VERSION 5.8 ;
BUSBITCHARS "[]" ;
DIVIDERCHAR "/" ;
UNITS
    DATABASE MICRONS 1000 ;
END UNITS

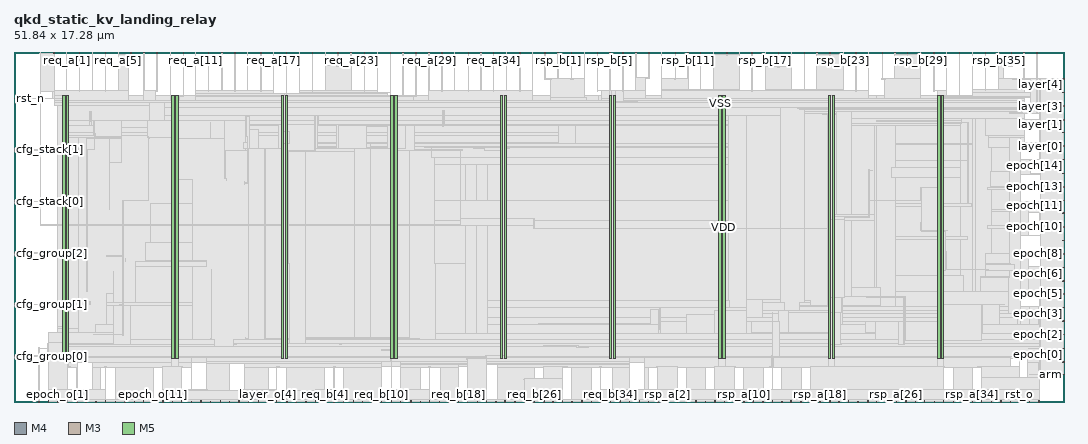
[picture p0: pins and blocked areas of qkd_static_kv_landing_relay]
MACRO qkd_static_kv_landing_relay
  FOREIGN qkd_static_kv_landing_relay 0 0 ;
  CLASS BLOCK ;
  SIZE 51.84 BY 17.28 ;
  PIN arm
    DIRECTION INPUT ;
    USE SIGNAL ;
    PORT
      LAYER M4 ;
        RECT  51.756 1.344 51.84 1.368 ;
    END
  END arm
  PIN arm_o
    DIRECTION OUTPUT ;
    USE SIGNAL ;
    PORT
      LAYER M3 ;
        RECT  1.224 0 1.242 0.038 ;
    END
  END arm_o
  PIN cfg_group[0]
    DIRECTION INPUT ;
    USE SIGNAL ;
    PORT
      LAYER M4 ;
        RECT  0 2.256 0.084 2.28 ;
    END
  END cfg_group[0]
  PIN cfg_group[1]
    DIRECTION INPUT ;
    USE SIGNAL ;
    PORT
      LAYER M4 ;
        RECT  0 4.8 0.084 4.824 ;
    END
  END cfg_group[1]
  PIN cfg_group[2]
    DIRECTION INPUT ;
    USE SIGNAL ;
    PORT
      LAYER M4 ;
        RECT  0 7.344 0.084 7.368 ;
    END
  END cfg_group[2]
  PIN cfg_stack[0]
    DIRECTION INPUT ;
    USE SIGNAL ;
    PORT
      LAYER M4 ;
        RECT  0 9.888 0.084 9.912 ;
    END
  END cfg_stack[0]
  PIN cfg_stack[1]
    DIRECTION INPUT ;
    USE SIGNAL ;
    PORT
      LAYER M4 ;
        RECT  0 12.432 0.084 12.456 ;
    END
  END cfg_stack[1]
  PIN ck
    DIRECTION INPUT ;
    USE SIGNAL ;
    PORT
      LAYER M3 ;
        RECT  1.296 17.242 1.314 17.28 ;
    END
  END ck
  PIN epoch[0]
    DIRECTION INPUT ;
    USE SIGNAL ;
    PORT
      LAYER M4 ;
        RECT  51.756 1.968 51.84 1.992 ;
    END
  END epoch[0]
  PIN epoch[10]
    DIRECTION INPUT ;
    USE SIGNAL ;
    PORT
      LAYER M4 ;
        RECT  51.756 8.64 51.84 8.664 ;
    END
  END epoch[10]
  PIN epoch[11]
    DIRECTION INPUT ;
    USE SIGNAL ;
    PORT
      LAYER M4 ;
        RECT  51.756 9.312 51.84 9.336 ;
    END
  END epoch[11]
  PIN epoch[12]
    DIRECTION INPUT ;
    USE SIGNAL ;
    PORT
      LAYER M4 ;
        RECT  51.756 9.936 51.84 9.96 ;
    END
  END epoch[12]
  PIN epoch[13]
    DIRECTION INPUT ;
    USE SIGNAL ;
    PORT
      LAYER M4 ;
        RECT  51.756 10.608 51.84 10.632 ;
    END
  END epoch[13]
  PIN epoch[14]
    DIRECTION INPUT ;
    USE SIGNAL ;
    PORT
      LAYER M4 ;
        RECT  51.756 11.28 51.84 11.304 ;
    END
  END epoch[14]
  PIN epoch[15]
    DIRECTION INPUT ;
    USE SIGNAL ;
    PORT
      LAYER M4 ;
        RECT  51.756 11.952 51.84 11.976 ;
    END
  END epoch[15]
  PIN epoch[1]
    DIRECTION INPUT ;
    USE SIGNAL ;
    PORT
      LAYER M4 ;
        RECT  51.756 2.64 51.84 2.664 ;
    END
  END epoch[1]
  PIN epoch[2]
    DIRECTION INPUT ;
    USE SIGNAL ;
    PORT
      LAYER M4 ;
        RECT  51.756 3.312 51.84 3.336 ;
    END
  END epoch[2]
  PIN epoch[3]
    DIRECTION INPUT ;
    USE SIGNAL ;
    PORT
      LAYER M4 ;
        RECT  51.756 3.984 51.84 4.008 ;
    END
  END epoch[3]
  PIN epoch[4]
    DIRECTION INPUT ;
    USE SIGNAL ;
    PORT
      LAYER M4 ;
        RECT  51.756 4.656 51.84 4.68 ;
    END
  END epoch[4]
  PIN epoch[5]
    DIRECTION INPUT ;
    USE SIGNAL ;
    PORT
      LAYER M4 ;
        RECT  51.756 5.328 51.84 5.352 ;
    END
  END epoch[5]
  PIN epoch[6]
    DIRECTION INPUT ;
    USE SIGNAL ;
    PORT
      LAYER M4 ;
        RECT  51.756 5.952 51.84 5.976 ;
    END
  END epoch[6]
  PIN epoch[7]
    DIRECTION INPUT ;
    USE SIGNAL ;
    PORT
      LAYER M4 ;
        RECT  51.756 6.624 51.84 6.648 ;
    END
  END epoch[7]
  PIN epoch[8]
    DIRECTION INPUT ;
    USE SIGNAL ;
    PORT
      LAYER M4 ;
        RECT  51.756 7.296 51.84 7.32 ;
    END
  END epoch[8]
  PIN epoch[9]
    DIRECTION INPUT ;
    USE SIGNAL ;
    PORT
      LAYER M4 ;
        RECT  51.756 7.968 51.84 7.992 ;
    END
  END epoch[9]
  PIN epoch_o[0]
    DIRECTION OUTPUT ;
    USE SIGNAL ;
    PORT
      LAYER M5 ;
        RECT  1.68 0 1.704 0.084 ;
    END
  END epoch_o[0]
  PIN epoch_o[10]
    DIRECTION OUTPUT ;
    USE SIGNAL ;
    PORT
      LAYER M5 ;
        RECT  6.384 0 6.408 0.084 ;
    END
  END epoch_o[10]
  PIN epoch_o[11]
    DIRECTION OUTPUT ;
    USE SIGNAL ;
    PORT
      LAYER M3 ;
        RECT  6.876 0 6.894 0.038 ;
    END
  END epoch_o[11]
  PIN epoch_o[12]
    DIRECTION OUTPUT ;
    USE SIGNAL ;
    PORT
      LAYER M5 ;
        RECT  7.344 0 7.368 0.084 ;
    END
  END epoch_o[12]
  PIN epoch_o[13]
    DIRECTION OUTPUT ;
    USE SIGNAL ;
    PORT
      LAYER M3 ;
        RECT  7.812 0 7.83 0.038 ;
    END
  END epoch_o[13]
  PIN epoch_o[14]
    DIRECTION OUTPUT ;
    USE SIGNAL ;
    PORT
      LAYER M5 ;
        RECT  8.256 0 8.28 0.084 ;
    END
  END epoch_o[14]
  PIN epoch_o[15]
    DIRECTION OUTPUT ;
    USE SIGNAL ;
    PORT
      LAYER M3 ;
        RECT  8.748 0 8.766 0.038 ;
    END
  END epoch_o[15]
  PIN epoch_o[1]
    DIRECTION OUTPUT ;
    USE SIGNAL ;
    PORT
      LAYER M3 ;
        RECT  2.16 0 2.178 0.038 ;
    END
  END epoch_o[1]
  PIN epoch_o[2]
    DIRECTION OUTPUT ;
    USE SIGNAL ;
    PORT
      LAYER M5 ;
        RECT  2.64 0 2.664 0.084 ;
    END
  END epoch_o[2]
  PIN epoch_o[3]
    DIRECTION OUTPUT ;
    USE SIGNAL ;
    PORT
      LAYER M3 ;
        RECT  3.096 0 3.114 0.038 ;
    END
  END epoch_o[3]
  PIN epoch_o[4]
    DIRECTION OUTPUT ;
    USE SIGNAL ;
    PORT
      LAYER M5 ;
        RECT  3.552 0 3.576 0.084 ;
    END
  END epoch_o[4]
  PIN epoch_o[5]
    DIRECTION OUTPUT ;
    USE SIGNAL ;
    PORT
      LAYER M3 ;
        RECT  4.032 0 4.05 0.038 ;
    END
  END epoch_o[5]
  PIN epoch_o[6]
    DIRECTION OUTPUT ;
    USE SIGNAL ;
    PORT
      LAYER M5 ;
        RECT  4.512 0 4.536 0.084 ;
    END
  END epoch_o[6]
  PIN epoch_o[7]
    DIRECTION OUTPUT ;
    USE SIGNAL ;
    PORT
      LAYER M3 ;
        RECT  5.004 0 5.022 0.038 ;
    END
  END epoch_o[7]
  PIN epoch_o[8]
    DIRECTION OUTPUT ;
    USE SIGNAL ;
    PORT
      LAYER M5 ;
        RECT  5.472 0 5.496 0.084 ;
    END
  END epoch_o[8]
  PIN epoch_o[9]
    DIRECTION OUTPUT ;
    USE SIGNAL ;
    PORT
      LAYER M3 ;
        RECT  5.94 0 5.958 0.038 ;
    END
  END epoch_o[9]
  PIN group_o[0]
    DIRECTION OUTPUT ;
    USE SIGNAL ;
    PORT
      LAYER M5 ;
        RECT  9.216 0 9.24 0.084 ;
    END
  END group_o[0]
  PIN group_o[1]
    DIRECTION OUTPUT ;
    USE SIGNAL ;
    PORT
      LAYER M3 ;
        RECT  9.684 0 9.702 0.038 ;
    END
  END group_o[1]
  PIN group_o[2]
    DIRECTION OUTPUT ;
    USE SIGNAL ;
    PORT
      LAYER M5 ;
        RECT  10.176 0 10.2 0.084 ;
    END
  END group_o[2]
  PIN layer[0]
    DIRECTION INPUT ;
    USE SIGNAL ;
    PORT
      LAYER M4 ;
        RECT  51.756 12.624 51.84 12.648 ;
    END
  END layer[0]
  PIN layer[1]
    DIRECTION INPUT ;
    USE SIGNAL ;
    PORT
      LAYER M4 ;
        RECT  51.756 13.296 51.84 13.32 ;
    END
  END layer[1]
  PIN layer[2]
    DIRECTION INPUT ;
    USE SIGNAL ;
    PORT
      LAYER M4 ;
        RECT  51.756 13.92 51.84 13.944 ;
    END
  END layer[2]
  PIN layer[3]
    DIRECTION INPUT ;
    USE SIGNAL ;
    PORT
      LAYER M4 ;
        RECT  51.756 14.592 51.84 14.616 ;
    END
  END layer[3]
  PIN layer[4]
    DIRECTION INPUT ;
    USE SIGNAL ;
    PORT
      LAYER M4 ;
        RECT  51.756 15.264 51.84 15.288 ;
    END
  END layer[4]
  PIN layer[5]
    DIRECTION INPUT ;
    USE SIGNAL ;
    PORT
      LAYER M4 ;
        RECT  51.756 15.936 51.84 15.96 ;
    END
  END layer[5]
  PIN layer_o[0]
    DIRECTION OUTPUT ;
    USE SIGNAL ;
    PORT
      LAYER M3 ;
        RECT  10.62 0 10.638 0.038 ;
    END
  END layer_o[0]
  PIN layer_o[1]
    DIRECTION OUTPUT ;
    USE SIGNAL ;
    PORT
      LAYER M5 ;
        RECT  11.088 0 11.112 0.084 ;
    END
  END layer_o[1]
  PIN layer_o[2]
    DIRECTION OUTPUT ;
    USE SIGNAL ;
    PORT
      LAYER M3 ;
        RECT  11.556 0 11.574 0.038 ;
    END
  END layer_o[2]
  PIN layer_o[3]
    DIRECTION OUTPUT ;
    USE SIGNAL ;
    PORT
      LAYER M5 ;
        RECT  12.048 0 12.072 0.084 ;
    END
  END layer_o[3]
  PIN layer_o[4]
    DIRECTION OUTPUT ;
    USE SIGNAL ;
    PORT
      LAYER M3 ;
        RECT  12.528 0 12.546 0.038 ;
    END
  END layer_o[4]
  PIN layer_o[5]
    DIRECTION OUTPUT ;
    USE SIGNAL ;
    PORT
      LAYER M5 ;
        RECT  12.96 0 12.984 0.084 ;
    END
  END layer_o[5]
  PIN req_a[0]
    DIRECTION INPUT ;
    USE SIGNAL ;
    PORT
      LAYER M5 ;
        RECT  1.968 17.196 1.992 17.28 ;
    END
  END req_a[0]
  PIN req_a[10]
    DIRECTION INPUT ;
    USE SIGNAL ;
    PORT
      LAYER M5 ;
        RECT  8.352 17.196 8.376 17.28 ;
    END
  END req_a[10]
  PIN req_a[11]
    DIRECTION INPUT ;
    USE SIGNAL ;
    PORT
      LAYER M3 ;
        RECT  8.964 17.242 8.982 17.28 ;
    END
  END req_a[11]
  PIN req_a[12]
    DIRECTION INPUT ;
    USE SIGNAL ;
    PORT
      LAYER M5 ;
        RECT  9.6 17.196 9.624 17.28 ;
    END
  END req_a[12]
  PIN req_a[13]
    DIRECTION INPUT ;
    USE SIGNAL ;
    PORT
      LAYER M3 ;
        RECT  10.26 17.242 10.278 17.28 ;
    END
  END req_a[13]
  PIN req_a[14]
    DIRECTION INPUT ;
    USE SIGNAL ;
    PORT
      LAYER M5 ;
        RECT  10.896 17.196 10.92 17.28 ;
    END
  END req_a[14]
  PIN req_a[15]
    DIRECTION INPUT ;
    USE SIGNAL ;
    PORT
      LAYER M3 ;
        RECT  11.52 17.242 11.538 17.28 ;
    END
  END req_a[15]
  PIN req_a[16]
    DIRECTION INPUT ;
    USE SIGNAL ;
    PORT
      LAYER M5 ;
        RECT  12.192 17.196 12.216 17.28 ;
    END
  END req_a[16]
  PIN req_a[17]
    DIRECTION INPUT ;
    USE SIGNAL ;
    PORT
      LAYER M3 ;
        RECT  12.816 17.242 12.834 17.28 ;
    END
  END req_a[17]
  PIN req_a[18]
    DIRECTION INPUT ;
    USE SIGNAL ;
    PORT
      LAYER M5 ;
        RECT  13.44 17.196 13.464 17.28 ;
    END
  END req_a[18]
  PIN req_a[19]
    DIRECTION INPUT ;
    USE SIGNAL ;
    PORT
      LAYER M3 ;
        RECT  14.076 17.242 14.094 17.28 ;
    END
  END req_a[19]
  PIN req_a[1]
    DIRECTION INPUT ;
    USE SIGNAL ;
    PORT
      LAYER M3 ;
        RECT  2.592 17.242 2.61 17.28 ;
    END
  END req_a[1]
  PIN req_a[20]
    DIRECTION INPUT ;
    USE SIGNAL ;
    PORT
      LAYER M5 ;
        RECT  14.736 17.196 14.76 17.28 ;
    END
  END req_a[20]
  PIN req_a[21]
    DIRECTION INPUT ;
    USE SIGNAL ;
    PORT
      LAYER M3 ;
        RECT  15.372 17.242 15.39 17.28 ;
    END
  END req_a[21]
  PIN req_a[22]
    DIRECTION INPUT ;
    USE SIGNAL ;
    PORT
      LAYER M5 ;
        RECT  15.984 17.196 16.008 17.28 ;
    END
  END req_a[22]
  PIN req_a[23]
    DIRECTION INPUT ;
    USE SIGNAL ;
    PORT
      LAYER M3 ;
        RECT  16.632 17.242 16.65 17.28 ;
    END
  END req_a[23]
  PIN req_a[24]
    DIRECTION INPUT ;
    USE SIGNAL ;
    PORT
      LAYER M5 ;
        RECT  17.28 17.196 17.304 17.28 ;
    END
  END req_a[24]
  PIN req_a[25]
    DIRECTION INPUT ;
    USE SIGNAL ;
    PORT
      LAYER M3 ;
        RECT  17.928 17.242 17.946 17.28 ;
    END
  END req_a[25]
  PIN req_a[26]
    DIRECTION INPUT ;
    USE SIGNAL ;
    PORT
      LAYER M5 ;
        RECT  18.576 17.196 18.6 17.28 ;
    END
  END req_a[26]
  PIN req_a[27]
    DIRECTION INPUT ;
    USE SIGNAL ;
    PORT
      LAYER M3 ;
        RECT  19.188 17.242 19.206 17.28 ;
    END
  END req_a[27]
  PIN req_a[28]
    DIRECTION INPUT ;
    USE SIGNAL ;
    PORT
      LAYER M5 ;
        RECT  19.824 17.196 19.848 17.28 ;
    END
  END req_a[28]
  PIN req_a[29]
    DIRECTION INPUT ;
    USE SIGNAL ;
    PORT
      LAYER M3 ;
        RECT  20.484 17.242 20.502 17.28 ;
    END
  END req_a[29]
  PIN req_a[2]
    DIRECTION INPUT ;
    USE SIGNAL ;
    PORT
      LAYER M5 ;
        RECT  3.216 17.196 3.24 17.28 ;
    END
  END req_a[2]
  PIN req_a[30]
    DIRECTION INPUT ;
    USE SIGNAL ;
    PORT
      LAYER M5 ;
        RECT  21.12 17.196 21.144 17.28 ;
    END
  END req_a[30]
  PIN req_a[31]
    DIRECTION INPUT ;
    USE SIGNAL ;
    PORT
      LAYER M3 ;
        RECT  21.744 17.242 21.762 17.28 ;
    END
  END req_a[31]
  PIN req_a[32]
    DIRECTION INPUT ;
    USE SIGNAL ;
    PORT
      LAYER M5 ;
        RECT  22.416 17.196 22.44 17.28 ;
    END
  END req_a[32]
  PIN req_a[33]
    DIRECTION INPUT ;
    USE SIGNAL ;
    PORT
      LAYER M3 ;
        RECT  23.04 17.242 23.058 17.28 ;
    END
  END req_a[33]
  PIN req_a[34]
    DIRECTION INPUT ;
    USE SIGNAL ;
    PORT
      LAYER M5 ;
        RECT  23.664 17.196 23.688 17.28 ;
    END
  END req_a[34]
  PIN req_a[35]
    DIRECTION INPUT ;
    USE SIGNAL ;
    PORT
      LAYER M3 ;
        RECT  24.3 17.242 24.318 17.28 ;
    END
  END req_a[35]
  PIN req_a[36]
    DIRECTION INPUT ;
    USE SIGNAL ;
    PORT
      LAYER M5 ;
        RECT  24.96 17.196 24.984 17.28 ;
    END
  END req_a[36]
  PIN req_a[37]
    DIRECTION INPUT ;
    USE SIGNAL ;
    PORT
      LAYER M3 ;
        RECT  25.596 17.242 25.614 17.28 ;
    END
  END req_a[37]
  PIN req_a[3]
    DIRECTION INPUT ;
    USE SIGNAL ;
    PORT
      LAYER M3 ;
        RECT  3.852 17.242 3.87 17.28 ;
    END
  END req_a[3]
  PIN req_a[4]
    DIRECTION INPUT ;
    USE SIGNAL ;
    PORT
      LAYER M5 ;
        RECT  4.512 17.196 4.536 17.28 ;
    END
  END req_a[4]
  PIN req_a[5]
    DIRECTION INPUT ;
    USE SIGNAL ;
    PORT
      LAYER M3 ;
        RECT  5.148 17.242 5.166 17.28 ;
    END
  END req_a[5]
  PIN req_a[6]
    DIRECTION INPUT ;
    USE SIGNAL ;
    PORT
      LAYER M5 ;
        RECT  5.76 17.196 5.784 17.28 ;
    END
  END req_a[6]
  PIN req_a[7]
    DIRECTION INPUT ;
    USE SIGNAL ;
    PORT
      LAYER M3 ;
        RECT  6.408 17.242 6.426 17.28 ;
    END
  END req_a[7]
  PIN req_a[8]
    DIRECTION INPUT ;
    USE SIGNAL ;
    PORT
      LAYER M5 ;
        RECT  7.056 17.196 7.08 17.28 ;
    END
  END req_a[8]
  PIN req_a[9]
    DIRECTION INPUT ;
    USE SIGNAL ;
    PORT
      LAYER M3 ;
        RECT  7.704 17.242 7.722 17.28 ;
    END
  END req_a[9]
  PIN req_b[0]
    DIRECTION OUTPUT ;
    USE SIGNAL ;
    PORT
      LAYER M3 ;
        RECT  13.464 0 13.482 0.038 ;
    END
  END req_b[0]
  PIN req_b[10]
    DIRECTION OUTPUT ;
    USE SIGNAL ;
    PORT
      LAYER M3 ;
        RECT  18.144 0 18.162 0.038 ;
    END
  END req_b[10]
  PIN req_b[11]
    DIRECTION OUTPUT ;
    USE SIGNAL ;
    PORT
      LAYER M5 ;
        RECT  18.624 0 18.648 0.084 ;
    END
  END req_b[11]
  PIN req_b[12]
    DIRECTION OUTPUT ;
    USE SIGNAL ;
    PORT
      LAYER M3 ;
        RECT  19.08 0 19.098 0.038 ;
    END
  END req_b[12]
  PIN req_b[13]
    DIRECTION OUTPUT ;
    USE SIGNAL ;
    PORT
      LAYER M5 ;
        RECT  19.584 0 19.608 0.084 ;
    END
  END req_b[13]
  PIN req_b[14]
    DIRECTION OUTPUT ;
    USE SIGNAL ;
    PORT
      LAYER M3 ;
        RECT  20.052 0 20.07 0.038 ;
    END
  END req_b[14]
  PIN req_b[15]
    DIRECTION OUTPUT ;
    USE SIGNAL ;
    PORT
      LAYER M5 ;
        RECT  20.496 0 20.52 0.084 ;
    END
  END req_b[15]
  PIN req_b[16]
    DIRECTION OUTPUT ;
    USE SIGNAL ;
    PORT
      LAYER M3 ;
        RECT  20.988 0 21.006 0.038 ;
    END
  END req_b[16]
  PIN req_b[17]
    DIRECTION OUTPUT ;
    USE SIGNAL ;
    PORT
      LAYER M5 ;
        RECT  21.456 0 21.48 0.084 ;
    END
  END req_b[17]
  PIN req_b[18]
    DIRECTION OUTPUT ;
    USE SIGNAL ;
    PORT
      LAYER M3 ;
        RECT  21.924 0 21.942 0.038 ;
    END
  END req_b[18]
  PIN req_b[19]
    DIRECTION OUTPUT ;
    USE SIGNAL ;
    PORT
      LAYER M5 ;
        RECT  22.368 0 22.392 0.084 ;
    END
  END req_b[19]
  PIN req_b[1]
    DIRECTION OUTPUT ;
    USE SIGNAL ;
    PORT
      LAYER M5 ;
        RECT  13.92 0 13.944 0.084 ;
    END
  END req_b[1]
  PIN req_b[20]
    DIRECTION OUTPUT ;
    USE SIGNAL ;
    PORT
      LAYER M3 ;
        RECT  22.86 0 22.878 0.038 ;
    END
  END req_b[20]
  PIN req_b[21]
    DIRECTION OUTPUT ;
    USE SIGNAL ;
    PORT
      LAYER M5 ;
        RECT  23.328 0 23.352 0.084 ;
    END
  END req_b[21]
  PIN req_b[22]
    DIRECTION OUTPUT ;
    USE SIGNAL ;
    PORT
      LAYER M3 ;
        RECT  23.796 0 23.814 0.038 ;
    END
  END req_b[22]
  PIN req_b[23]
    DIRECTION OUTPUT ;
    USE SIGNAL ;
    PORT
      LAYER M5 ;
        RECT  24.24 0 24.264 0.084 ;
    END
  END req_b[23]
  PIN req_b[24]
    DIRECTION OUTPUT ;
    USE SIGNAL ;
    PORT
      LAYER M3 ;
        RECT  24.732 0 24.75 0.038 ;
    END
  END req_b[24]
  PIN req_b[25]
    DIRECTION OUTPUT ;
    USE SIGNAL ;
    PORT
      LAYER M5 ;
        RECT  25.2 0 25.224 0.084 ;
    END
  END req_b[25]
  PIN req_b[26]
    DIRECTION OUTPUT ;
    USE SIGNAL ;
    PORT
      LAYER M3 ;
        RECT  25.668 0 25.686 0.038 ;
    END
  END req_b[26]
  PIN req_b[27]
    DIRECTION OUTPUT ;
    USE SIGNAL ;
    PORT
      LAYER M5 ;
        RECT  26.16 0 26.184 0.084 ;
    END
  END req_b[27]
  PIN req_b[28]
    DIRECTION OUTPUT ;
    USE SIGNAL ;
    PORT
      LAYER M3 ;
        RECT  26.604 0 26.622 0.038 ;
    END
  END req_b[28]
  PIN req_b[29]
    DIRECTION OUTPUT ;
    USE SIGNAL ;
    PORT
      LAYER M5 ;
        RECT  27.072 0 27.096 0.084 ;
    END
  END req_b[29]
  PIN req_b[2]
    DIRECTION OUTPUT ;
    USE SIGNAL ;
    PORT
      LAYER M3 ;
        RECT  14.4 0 14.418 0.038 ;
    END
  END req_b[2]
  PIN req_b[30]
    DIRECTION OUTPUT ;
    USE SIGNAL ;
    PORT
      LAYER M3 ;
        RECT  27.54 0 27.558 0.038 ;
    END
  END req_b[30]
  PIN req_b[31]
    DIRECTION OUTPUT ;
    USE SIGNAL ;
    PORT
      LAYER M5 ;
        RECT  28.032 0 28.056 0.084 ;
    END
  END req_b[31]
  PIN req_b[32]
    DIRECTION OUTPUT ;
    USE SIGNAL ;
    PORT
      LAYER M3 ;
        RECT  28.512 0 28.53 0.038 ;
    END
  END req_b[32]
  PIN req_b[33]
    DIRECTION OUTPUT ;
    USE SIGNAL ;
    PORT
      LAYER M5 ;
        RECT  28.944 0 28.968 0.084 ;
    END
  END req_b[33]
  PIN req_b[34]
    DIRECTION OUTPUT ;
    USE SIGNAL ;
    PORT
      LAYER M3 ;
        RECT  29.448 0 29.466 0.038 ;
    END
  END req_b[34]
  PIN req_b[35]
    DIRECTION OUTPUT ;
    USE SIGNAL ;
    PORT
      LAYER M5 ;
        RECT  29.904 0 29.928 0.084 ;
    END
  END req_b[35]
  PIN req_b[36]
    DIRECTION OUTPUT ;
    USE SIGNAL ;
    PORT
      LAYER M3 ;
        RECT  30.384 0 30.402 0.038 ;
    END
  END req_b[36]
  PIN req_b[37]
    DIRECTION OUTPUT ;
    USE SIGNAL ;
    PORT
      LAYER M5 ;
        RECT  30.864 0 30.888 0.084 ;
    END
  END req_b[37]
  PIN req_b[3]
    DIRECTION OUTPUT ;
    USE SIGNAL ;
    PORT
      LAYER M5 ;
        RECT  14.88 0 14.904 0.084 ;
    END
  END req_b[3]
  PIN req_b[4]
    DIRECTION OUTPUT ;
    USE SIGNAL ;
    PORT
      LAYER M3 ;
        RECT  15.336 0 15.354 0.038 ;
    END
  END req_b[4]
  PIN req_b[5]
    DIRECTION OUTPUT ;
    USE SIGNAL ;
    PORT
      LAYER M5 ;
        RECT  15.792 0 15.816 0.084 ;
    END
  END req_b[5]
  PIN req_b[6]
    DIRECTION OUTPUT ;
    USE SIGNAL ;
    PORT
      LAYER M3 ;
        RECT  16.272 0 16.29 0.038 ;
    END
  END req_b[6]
  PIN req_b[7]
    DIRECTION OUTPUT ;
    USE SIGNAL ;
    PORT
      LAYER M5 ;
        RECT  16.752 0 16.776 0.084 ;
    END
  END req_b[7]
  PIN req_b[8]
    DIRECTION OUTPUT ;
    USE SIGNAL ;
    PORT
      LAYER M3 ;
        RECT  17.208 0 17.226 0.038 ;
    END
  END req_b[8]
  PIN req_b[9]
    DIRECTION OUTPUT ;
    USE SIGNAL ;
    PORT
      LAYER M5 ;
        RECT  17.664 0 17.688 0.084 ;
    END
  END req_b[9]
  PIN rsp_a[0]
    DIRECTION INPUT ;
    USE SIGNAL ;
    PORT
      LAYER M3 ;
        RECT  31.32 0 31.338 0.038 ;
    END
  END rsp_a[0]
  PIN rsp_a[10]
    DIRECTION INPUT ;
    USE SIGNAL ;
    PORT
      LAYER M3 ;
        RECT  36.036 0 36.054 0.038 ;
    END
  END rsp_a[10]
  PIN rsp_a[11]
    DIRECTION INPUT ;
    USE SIGNAL ;
    PORT
      LAYER M5 ;
        RECT  36.48 0 36.504 0.084 ;
    END
  END rsp_a[11]
  PIN rsp_a[12]
    DIRECTION INPUT ;
    USE SIGNAL ;
    PORT
      LAYER M3 ;
        RECT  36.972 0 36.99 0.038 ;
    END
  END rsp_a[12]
  PIN rsp_a[13]
    DIRECTION INPUT ;
    USE SIGNAL ;
    PORT
      LAYER M5 ;
        RECT  37.44 0 37.464 0.084 ;
    END
  END rsp_a[13]
  PIN rsp_a[14]
    DIRECTION INPUT ;
    USE SIGNAL ;
    PORT
      LAYER M3 ;
        RECT  37.908 0 37.926 0.038 ;
    END
  END rsp_a[14]
  PIN rsp_a[15]
    DIRECTION INPUT ;
    USE SIGNAL ;
    PORT
      LAYER M5 ;
        RECT  38.352 0 38.376 0.084 ;
    END
  END rsp_a[15]
  PIN rsp_a[16]
    DIRECTION INPUT ;
    USE SIGNAL ;
    PORT
      LAYER M3 ;
        RECT  38.844 0 38.862 0.038 ;
    END
  END rsp_a[16]
  PIN rsp_a[17]
    DIRECTION INPUT ;
    USE SIGNAL ;
    PORT
      LAYER M5 ;
        RECT  39.312 0 39.336 0.084 ;
    END
  END rsp_a[17]
  PIN rsp_a[18]
    DIRECTION INPUT ;
    USE SIGNAL ;
    PORT
      LAYER M3 ;
        RECT  39.78 0 39.798 0.038 ;
    END
  END rsp_a[18]
  PIN rsp_a[19]
    DIRECTION INPUT ;
    USE SIGNAL ;
    PORT
      LAYER M5 ;
        RECT  40.272 0 40.296 0.084 ;
    END
  END rsp_a[19]
  PIN rsp_a[1]
    DIRECTION INPUT ;
    USE SIGNAL ;
    PORT
      LAYER M5 ;
        RECT  31.776 0 31.8 0.084 ;
    END
  END rsp_a[1]
  PIN rsp_a[20]
    DIRECTION INPUT ;
    USE SIGNAL ;
    PORT
      LAYER M3 ;
        RECT  40.716 0 40.734 0.038 ;
    END
  END rsp_a[20]
  PIN rsp_a[21]
    DIRECTION INPUT ;
    USE SIGNAL ;
    PORT
      LAYER M5 ;
        RECT  41.184 0 41.208 0.084 ;
    END
  END rsp_a[21]
  PIN rsp_a[22]
    DIRECTION INPUT ;
    USE SIGNAL ;
    PORT
      LAYER M3 ;
        RECT  41.652 0 41.67 0.038 ;
    END
  END rsp_a[22]
  PIN rsp_a[23]
    DIRECTION INPUT ;
    USE SIGNAL ;
    PORT
      LAYER M5 ;
        RECT  42.144 0 42.168 0.084 ;
    END
  END rsp_a[23]
  PIN rsp_a[24]
    DIRECTION INPUT ;
    USE SIGNAL ;
    PORT
      LAYER M3 ;
        RECT  42.588 0 42.606 0.038 ;
    END
  END rsp_a[24]
  PIN rsp_a[25]
    DIRECTION INPUT ;
    USE SIGNAL ;
    PORT
      LAYER M5 ;
        RECT  43.056 0 43.08 0.084 ;
    END
  END rsp_a[25]
  PIN rsp_a[26]
    DIRECTION INPUT ;
    USE SIGNAL ;
    PORT
      LAYER M3 ;
        RECT  43.56 0 43.578 0.038 ;
    END
  END rsp_a[26]
  PIN rsp_a[27]
    DIRECTION INPUT ;
    USE SIGNAL ;
    PORT
      LAYER M5 ;
        RECT  44.016 0 44.04 0.084 ;
    END
  END rsp_a[27]
  PIN rsp_a[28]
    DIRECTION INPUT ;
    USE SIGNAL ;
    PORT
      LAYER M3 ;
        RECT  44.496 0 44.514 0.038 ;
    END
  END rsp_a[28]
  PIN rsp_a[29]
    DIRECTION INPUT ;
    USE SIGNAL ;
    PORT
      LAYER M5 ;
        RECT  44.928 0 44.952 0.084 ;
    END
  END rsp_a[29]
  PIN rsp_a[2]
    DIRECTION INPUT ;
    USE SIGNAL ;
    PORT
      LAYER M3 ;
        RECT  32.256 0 32.274 0.038 ;
    END
  END rsp_a[2]
  PIN rsp_a[30]
    DIRECTION INPUT ;
    USE SIGNAL ;
    PORT
      LAYER M3 ;
        RECT  45.432 0 45.45 0.038 ;
    END
  END rsp_a[30]
  PIN rsp_a[31]
    DIRECTION INPUT ;
    USE SIGNAL ;
    PORT
      LAYER M5 ;
        RECT  45.888 0 45.912 0.084 ;
    END
  END rsp_a[31]
  PIN rsp_a[32]
    DIRECTION INPUT ;
    USE SIGNAL ;
    PORT
      LAYER M3 ;
        RECT  46.368 0 46.386 0.038 ;
    END
  END rsp_a[32]
  PIN rsp_a[33]
    DIRECTION INPUT ;
    USE SIGNAL ;
    PORT
      LAYER M5 ;
        RECT  46.848 0 46.872 0.084 ;
    END
  END rsp_a[33]
  PIN rsp_a[34]
    DIRECTION INPUT ;
    USE SIGNAL ;
    PORT
      LAYER M3 ;
        RECT  47.304 0 47.322 0.038 ;
    END
  END rsp_a[34]
  PIN rsp_a[35]
    DIRECTION INPUT ;
    USE SIGNAL ;
    PORT
      LAYER M5 ;
        RECT  47.76 0 47.784 0.084 ;
    END
  END rsp_a[35]
  PIN rsp_a[36]
    DIRECTION INPUT ;
    USE SIGNAL ;
    PORT
      LAYER M3 ;
        RECT  48.24 0 48.258 0.038 ;
    END
  END rsp_a[36]
  PIN rsp_a[37]
    DIRECTION INPUT ;
    USE SIGNAL ;
    PORT
      LAYER M5 ;
        RECT  48.72 0 48.744 0.084 ;
    END
  END rsp_a[37]
  PIN rsp_a[38]
    DIRECTION INPUT ;
    USE SIGNAL ;
    PORT
      LAYER M3 ;
        RECT  49.176 0 49.194 0.038 ;
    END
  END rsp_a[38]
  PIN rsp_a[3]
    DIRECTION INPUT ;
    USE SIGNAL ;
    PORT
      LAYER M5 ;
        RECT  32.736 0 32.76 0.084 ;
    END
  END rsp_a[3]
  PIN rsp_a[4]
    DIRECTION INPUT ;
    USE SIGNAL ;
    PORT
      LAYER M3 ;
        RECT  33.192 0 33.21 0.038 ;
    END
  END rsp_a[4]
  PIN rsp_a[5]
    DIRECTION INPUT ;
    USE SIGNAL ;
    PORT
      LAYER M5 ;
        RECT  33.648 0 33.672 0.084 ;
    END
  END rsp_a[5]
  PIN rsp_a[6]
    DIRECTION INPUT ;
    USE SIGNAL ;
    PORT
      LAYER M3 ;
        RECT  34.128 0 34.146 0.038 ;
    END
  END rsp_a[6]
  PIN rsp_a[7]
    DIRECTION INPUT ;
    USE SIGNAL ;
    PORT
      LAYER M5 ;
        RECT  34.608 0 34.632 0.084 ;
    END
  END rsp_a[7]
  PIN rsp_a[8]
    DIRECTION INPUT ;
    USE SIGNAL ;
    PORT
      LAYER M3 ;
        RECT  35.064 0 35.082 0.038 ;
    END
  END rsp_a[8]
  PIN rsp_a[9]
    DIRECTION INPUT ;
    USE SIGNAL ;
    PORT
      LAYER M5 ;
        RECT  35.568 0 35.592 0.084 ;
    END
  END rsp_a[9]
  PIN rsp_b[0]
    DIRECTION OUTPUT ;
    USE SIGNAL ;
    PORT
      LAYER M5 ;
        RECT  26.208 17.196 26.232 17.28 ;
    END
  END rsp_b[0]
  PIN rsp_b[10]
    DIRECTION OUTPUT ;
    USE SIGNAL ;
    PORT
      LAYER M5 ;
        RECT  32.64 17.196 32.664 17.28 ;
    END
  END rsp_b[10]
  PIN rsp_b[11]
    DIRECTION OUTPUT ;
    USE SIGNAL ;
    PORT
      LAYER M3 ;
        RECT  33.264 17.242 33.282 17.28 ;
    END
  END rsp_b[11]
  PIN rsp_b[12]
    DIRECTION OUTPUT ;
    USE SIGNAL ;
    PORT
      LAYER M5 ;
        RECT  33.888 17.196 33.912 17.28 ;
    END
  END rsp_b[12]
  PIN rsp_b[13]
    DIRECTION OUTPUT ;
    USE SIGNAL ;
    PORT
      LAYER M3 ;
        RECT  34.524 17.242 34.542 17.28 ;
    END
  END rsp_b[13]
  PIN rsp_b[14]
    DIRECTION OUTPUT ;
    USE SIGNAL ;
    PORT
      LAYER M5 ;
        RECT  35.184 17.196 35.208 17.28 ;
    END
  END rsp_b[14]
  PIN rsp_b[15]
    DIRECTION OUTPUT ;
    USE SIGNAL ;
    PORT
      LAYER M3 ;
        RECT  35.82 17.242 35.838 17.28 ;
    END
  END rsp_b[15]
  PIN rsp_b[16]
    DIRECTION OUTPUT ;
    USE SIGNAL ;
    PORT
      LAYER M5 ;
        RECT  36.432 17.196 36.456 17.28 ;
    END
  END rsp_b[16]
  PIN rsp_b[17]
    DIRECTION OUTPUT ;
    USE SIGNAL ;
    PORT
      LAYER M3 ;
        RECT  37.08 17.242 37.098 17.28 ;
    END
  END rsp_b[17]
  PIN rsp_b[18]
    DIRECTION OUTPUT ;
    USE SIGNAL ;
    PORT
      LAYER M5 ;
        RECT  37.728 17.196 37.752 17.28 ;
    END
  END rsp_b[18]
  PIN rsp_b[19]
    DIRECTION OUTPUT ;
    USE SIGNAL ;
    PORT
      LAYER M3 ;
        RECT  38.376 17.242 38.394 17.28 ;
    END
  END rsp_b[19]
  PIN rsp_b[1]
    DIRECTION OUTPUT ;
    USE SIGNAL ;
    PORT
      LAYER M3 ;
        RECT  26.856 17.242 26.874 17.28 ;
    END
  END rsp_b[1]
  PIN rsp_b[20]
    DIRECTION OUTPUT ;
    USE SIGNAL ;
    PORT
      LAYER M5 ;
        RECT  39.024 17.196 39.048 17.28 ;
    END
  END rsp_b[20]
  PIN rsp_b[21]
    DIRECTION OUTPUT ;
    USE SIGNAL ;
    PORT
      LAYER M3 ;
        RECT  39.636 17.242 39.654 17.28 ;
    END
  END rsp_b[21]
  PIN rsp_b[22]
    DIRECTION OUTPUT ;
    USE SIGNAL ;
    PORT
      LAYER M5 ;
        RECT  40.272 17.196 40.296 17.28 ;
    END
  END rsp_b[22]
  PIN rsp_b[23]
    DIRECTION OUTPUT ;
    USE SIGNAL ;
    PORT
      LAYER M3 ;
        RECT  40.932 17.242 40.95 17.28 ;
    END
  END rsp_b[23]
  PIN rsp_b[24]
    DIRECTION OUTPUT ;
    USE SIGNAL ;
    PORT
      LAYER M5 ;
        RECT  41.568 17.196 41.592 17.28 ;
    END
  END rsp_b[24]
  PIN rsp_b[25]
    DIRECTION OUTPUT ;
    USE SIGNAL ;
    PORT
      LAYER M3 ;
        RECT  42.192 17.242 42.21 17.28 ;
    END
  END rsp_b[25]
  PIN rsp_b[26]
    DIRECTION OUTPUT ;
    USE SIGNAL ;
    PORT
      LAYER M5 ;
        RECT  42.864 17.196 42.888 17.28 ;
    END
  END rsp_b[26]
  PIN rsp_b[27]
    DIRECTION OUTPUT ;
    USE SIGNAL ;
    PORT
      LAYER M3 ;
        RECT  43.488 17.242 43.506 17.28 ;
    END
  END rsp_b[27]
  PIN rsp_b[28]
    DIRECTION OUTPUT ;
    USE SIGNAL ;
    PORT
      LAYER M5 ;
        RECT  44.112 17.196 44.136 17.28 ;
    END
  END rsp_b[28]
  PIN rsp_b[29]
    DIRECTION OUTPUT ;
    USE SIGNAL ;
    PORT
      LAYER M3 ;
        RECT  44.748 17.242 44.766 17.28 ;
    END
  END rsp_b[29]
  PIN rsp_b[2]
    DIRECTION OUTPUT ;
    USE SIGNAL ;
    PORT
      LAYER M5 ;
        RECT  27.504 17.196 27.528 17.28 ;
    END
  END rsp_b[2]
  PIN rsp_b[30]
    DIRECTION OUTPUT ;
    USE SIGNAL ;
    PORT
      LAYER M5 ;
        RECT  45.408 17.196 45.432 17.28 ;
    END
  END rsp_b[30]
  PIN rsp_b[31]
    DIRECTION OUTPUT ;
    USE SIGNAL ;
    PORT
      LAYER M3 ;
        RECT  46.044 17.242 46.062 17.28 ;
    END
  END rsp_b[31]
  PIN rsp_b[32]
    DIRECTION OUTPUT ;
    USE SIGNAL ;
    PORT
      LAYER M5 ;
        RECT  46.656 17.196 46.68 17.28 ;
    END
  END rsp_b[32]
  PIN rsp_b[33]
    DIRECTION OUTPUT ;
    USE SIGNAL ;
    PORT
      LAYER M3 ;
        RECT  47.304 17.242 47.322 17.28 ;
    END
  END rsp_b[33]
  PIN rsp_b[34]
    DIRECTION OUTPUT ;
    USE SIGNAL ;
    PORT
      LAYER M5 ;
        RECT  47.952 17.196 47.976 17.28 ;
    END
  END rsp_b[34]
  PIN rsp_b[35]
    DIRECTION OUTPUT ;
    USE SIGNAL ;
    PORT
      LAYER M3 ;
        RECT  48.6 17.242 48.618 17.28 ;
    END
  END rsp_b[35]
  PIN rsp_b[36]
    DIRECTION OUTPUT ;
    USE SIGNAL ;
    PORT
      LAYER M5 ;
        RECT  49.248 17.196 49.272 17.28 ;
    END
  END rsp_b[36]
  PIN rsp_b[37]
    DIRECTION OUTPUT ;
    USE SIGNAL ;
    PORT
      LAYER M3 ;
        RECT  49.86 17.242 49.878 17.28 ;
    END
  END rsp_b[37]
  PIN rsp_b[38]
    DIRECTION OUTPUT ;
    USE SIGNAL ;
    PORT
      LAYER M5 ;
        RECT  50.496 17.196 50.52 17.28 ;
    END
  END rsp_b[38]
  PIN rsp_b[3]
    DIRECTION OUTPUT ;
    USE SIGNAL ;
    PORT
      LAYER M3 ;
        RECT  28.152 17.242 28.17 17.28 ;
    END
  END rsp_b[3]
  PIN rsp_b[4]
    DIRECTION OUTPUT ;
    USE SIGNAL ;
    PORT
      LAYER M5 ;
        RECT  28.8 17.196 28.824 17.28 ;
    END
  END rsp_b[4]
  PIN rsp_b[5]
    DIRECTION OUTPUT ;
    USE SIGNAL ;
    PORT
      LAYER M3 ;
        RECT  29.412 17.242 29.43 17.28 ;
    END
  END rsp_b[5]
  PIN rsp_b[6]
    DIRECTION OUTPUT ;
    USE SIGNAL ;
    PORT
      LAYER M5 ;
        RECT  30.048 17.196 30.072 17.28 ;
    END
  END rsp_b[6]
  PIN rsp_b[7]
    DIRECTION OUTPUT ;
    USE SIGNAL ;
    PORT
      LAYER M3 ;
        RECT  30.708 17.242 30.726 17.28 ;
    END
  END rsp_b[7]
  PIN rsp_b[8]
    DIRECTION OUTPUT ;
    USE SIGNAL ;
    PORT
      LAYER M5 ;
        RECT  31.344 17.196 31.368 17.28 ;
    END
  END rsp_b[8]
  PIN rsp_b[9]
    DIRECTION OUTPUT ;
    USE SIGNAL ;
    PORT
      LAYER M3 ;
        RECT  31.968 17.242 31.986 17.28 ;
    END
  END rsp_b[9]
  PIN rst_n
    DIRECTION INPUT ;
    USE SIGNAL ;
    PORT
      LAYER M4 ;
        RECT  0 14.976 0.084 15 ;
    END
  END rst_n
  PIN rst_o
    DIRECTION OUTPUT ;
    USE SIGNAL ;
    PORT
      LAYER M5 ;
        RECT  49.632 0 49.656 0.084 ;
    END
  END rst_o
  PIN stack_o[0]
    DIRECTION OUTPUT ;
    USE SIGNAL ;
    PORT
      LAYER M3 ;
        RECT  50.112 0 50.13 0.038 ;
    END
  END stack_o[0]
  PIN stack_o[1]
    DIRECTION OUTPUT ;
    USE SIGNAL ;
    PORT
      LAYER M5 ;
        RECT  50.592 0 50.616 0.084 ;
    END
  END stack_o[1]
  PIN VDD
    DIRECTION INOUT ;
    USE POWER ;
    PORT
      LAYER M5 ;
        RECT  45.792 2.151 45.912 15.129 ;
        RECT  40.392 2.151 40.512 15.129 ;
        RECT  34.992 2.151 35.112 15.129 ;
        RECT  29.592 2.151 29.712 15.129 ;
        RECT  24.192 2.151 24.312 15.129 ;
        RECT  18.792 2.151 18.912 15.129 ;
        RECT  13.392 2.151 13.512 15.129 ;
        RECT  7.992 2.151 8.112 15.129 ;
        RECT  2.592 2.151 2.712 15.129 ;
    END
  END VDD
  PIN VSS
    DIRECTION INOUT ;
    USE GROUND ;
    PORT
      LAYER M5 ;
        RECT  45.6 2.137 45.72 15.143 ;
        RECT  40.2 2.137 40.32 15.143 ;
        RECT  34.8 2.137 34.92 15.143 ;
        RECT  29.4 2.137 29.52 15.143 ;
        RECT  24 2.137 24.12 15.143 ;
        RECT  18.6 2.137 18.72 15.143 ;
        RECT  13.2 2.137 13.32 15.143 ;
        RECT  7.8 2.137 7.92 15.143 ;
        RECT  2.4 2.137 2.52 15.143 ;
    END
  END VSS
  OBS
    LAYER RVTN ;
     RECT  2.16 2.16 49.68 2.295 ;
     RECT  2.16 2.565 49.68 2.835 ;
     RECT  2.16 3.105 49.68 3.375 ;
     RECT  2.16 3.645 49.68 3.915 ;
     RECT  2.16 4.185 49.68 4.455 ;
     RECT  2.16 4.725 49.68 4.995 ;
     RECT  2.16 5.265 49.68 5.535 ;
     RECT  2.16 5.805 49.68 6.075 ;
     RECT  2.16 6.345 49.68 6.615 ;
     RECT  2.16 6.885 49.68 7.155 ;
     RECT  2.16 7.425 49.68 7.695 ;
     RECT  2.16 7.965 49.68 8.235 ;
     RECT  2.16 8.505 49.68 8.775 ;
     RECT  2.16 9.045 49.68 9.315 ;
     RECT  2.16 9.585 49.68 9.855 ;
     RECT  2.16 10.125 49.68 10.395 ;
     RECT  2.16 10.665 49.68 10.935 ;
     RECT  2.16 11.205 49.68 11.475 ;
     RECT  2.16 11.745 49.68 12.015 ;
     RECT  2.16 12.285 49.68 12.555 ;
     RECT  2.16 12.825 49.68 13.095 ;
     RECT  2.16 13.365 49.68 13.635 ;
     RECT  2.16 13.905 49.68 14.175 ;
     RECT  2.16 14.445 49.68 14.715 ;
     RECT  2.16 14.985 49.68 15.12 ;
    LAYER RVTP ;
     RECT  2.16 2.295 49.68 2.565 ;
     RECT  2.16 2.835 49.68 3.105 ;
     RECT  2.16 3.375 49.68 3.645 ;
     RECT  2.16 3.915 49.68 4.185 ;
     RECT  2.16 4.455 49.68 4.725 ;
     RECT  2.16 4.995 49.68 5.265 ;
     RECT  2.16 5.535 49.68 5.805 ;
     RECT  2.16 6.075 49.68 6.345 ;
     RECT  2.16 6.615 49.68 6.885 ;
     RECT  2.16 7.155 49.68 7.425 ;
     RECT  2.16 7.695 49.68 7.965 ;
     RECT  2.16 8.235 49.68 8.505 ;
     RECT  2.16 8.775 49.68 9.045 ;
     RECT  2.16 9.315 49.68 9.585 ;
     RECT  2.16 9.855 49.68 10.125 ;
     RECT  2.16 10.395 49.68 10.665 ;
     RECT  2.16 10.935 49.68 11.205 ;
     RECT  2.16 11.475 49.68 11.745 ;
     RECT  2.16 12.015 49.68 12.285 ;
     RECT  2.16 12.555 49.68 12.825 ;
     RECT  2.16 13.095 49.68 13.365 ;
     RECT  2.16 13.635 49.68 13.905 ;
     RECT  2.16 14.175 49.68 14.445 ;
     RECT  2.16 14.715 49.68 14.985 ;
    LAYER M1 ;
     RECT  2.16 2.151 49.68 15.129 ;
    LAYER M2 ;
     RECT  1.219 2.646 1.687 2.664 ;
     RECT  1.687 2.646 2.155 3.402 ;
     RECT  2.155 2.646 2.16 3.744 ;
     RECT  1.975 14.652 2.16 14.67 ;
     RECT  2.16 2.151 3.163 15.129 ;
     RECT  4.027 0.036 4.271 0.054 ;
     RECT  7.807 0.036 7.979 0.054 ;
     RECT  3.163 1.962 8.095 15.129 ;
     RECT  8.095 1.926 11.587 15.129 ;
     RECT  14.395 0.036 14.495 0.054 ;
     RECT  11.587 1.881 14.827 15.129 ;
     RECT  17.203 0.036 17.339 0.054 ;
     RECT  20.983 0.036 21.083 0.054 ;
     RECT  14.827 1.764 22.811 15.129 ;
     RECT  22.811 1.836 23.819 15.129 ;
     RECT  23.791 0.036 23.891 0.054 ;
     RECT  24.727 0.036 24.971 0.054 ;
     RECT  23.819 1.881 26.743 15.129 ;
     RECT  26.743 1.836 28.859 15.129 ;
     RECT  28.859 1.926 29.399 15.129 ;
     RECT  29.399 1.962 29.407 15.129 ;
     RECT  29.443 0.036 29.579 0.054 ;
     RECT  29.407 1.962 29.579 15.21 ;
     RECT  29.579 1.962 42.575 15.129 ;
     RECT  42.575 2.151 47.299 15.129 ;
     RECT  47.299 2.151 47.471 15.399 ;
     RECT  47.471 2.151 49.68 15.129 ;
     RECT  49.68 14.724 49.811 15.048 ;
     RECT  49.68 12.798 49.883 13.932 ;
     RECT  49.68 5.508 50.099 7.416 ;
     RECT  49.68 8.208 50.099 9.918 ;
     RECT  50.035 0.036 50.135 0.054 ;
     RECT  49.68 2.646 50.135 4.716 ;
     RECT  49.68 11.25 50.171 11.97 ;
     RECT  49.811 15.03 50.207 15.048 ;
     RECT  50.135 2.772 50.603 4.716 ;
     RECT  50.603 3.078 50.675 4.716 ;
     RECT  50.099 5.508 50.675 6.714 ;
     RECT  50.099 9.36 50.675 9.918 ;
     RECT  49.883 12.798 50.675 12.816 ;
     RECT  49.883 13.608 50.675 13.932 ;
     RECT  50.675 6.048 50.711 6.714 ;
     RECT  50.099 8.208 50.711 8.226 ;
     RECT  50.675 9.9 50.711 9.918 ;
     RECT  50.171 11.25 50.711 11.268 ;
     RECT  50.675 13.914 50.711 13.932 ;
    LAYER M3 ;
     RECT  4.032 0.012 4.05 0.031 ;
     RECT  7.812 0.012 7.83 0.031 ;
     RECT  14.4 0.012 14.418 0.031 ;
     RECT  17.208 0.012 17.226 0.031 ;
     RECT  20.988 0.012 21.006 0.031 ;
     RECT  23.796 0.012 23.814 0.031 ;
     RECT  24.732 0.012 24.75 0.031 ;
     RECT  25.668 0.012 25.686 0.031 ;
     RECT  29.448 0.012 29.466 0.031 ;
     RECT  50.112 0.012 50.13 0.031 ;
     RECT  7.812 0.031 7.974 0.059 ;
     RECT  20.988 0.031 21.078 0.059 ;
     RECT  23.796 0.031 23.886 0.059 ;
     RECT  29.448 0.031 29.574 0.059 ;
     RECT  50.04 0.031 50.13 0.059 ;
     RECT  5.004 0.012 5.022 0.091 ;
     RECT  5.94 0.012 5.958 0.091 ;
     RECT  6.876 0.012 6.894 0.091 ;
     RECT  13.464 0.012 13.482 0.091 ;
     RECT  14.4 0.031 14.49 0.091 ;
     RECT  16.272 0.012 16.29 0.091 ;
     RECT  17.208 0.031 17.334 0.091 ;
     RECT  18.144 0.012 18.162 0.091 ;
     RECT  21.06 0.059 21.078 0.091 ;
     RECT  21.924 0.012 21.942 0.091 ;
     RECT  23.868 0.059 23.886 0.091 ;
     RECT  24.732 0.031 25.686 0.091 ;
     RECT  27.54 0.012 27.558 0.091 ;
     RECT  28.512 0.012 28.53 0.091 ;
     RECT  9.684 0.012 9.702 0.523 ;
     RECT  10.62 0.012 10.638 0.523 ;
     RECT  4.032 0.031 4.266 0.571 ;
     RECT  9.684 0.523 10.638 0.571 ;
     RECT  11.556 0.012 11.574 0.571 ;
     RECT  12.528 0.012 12.546 0.571 ;
     RECT  13.464 0.091 14.49 0.571 ;
     RECT  15.336 0.012 15.354 0.571 ;
     RECT  19.08 0.012 19.098 0.571 ;
     RECT  20.052 0.012 20.07 0.571 ;
     RECT  29.556 0.059 29.574 0.571 ;
     RECT  30.384 0.012 30.402 0.571 ;
     RECT  31.32 0.012 31.338 0.571 ;
     RECT  33.192 0.012 33.21 0.571 ;
     RECT  34.128 0.012 34.146 0.571 ;
     RECT  36.036 0.012 36.054 0.571 ;
     RECT  36.972 0.012 36.99 0.571 ;
     RECT  37.908 0.012 37.926 0.571 ;
     RECT  38.844 0.012 38.862 0.571 ;
     RECT  46.368 0.012 46.386 0.571 ;
     RECT  47.304 0.012 47.322 0.571 ;
     RECT  50.04 0.059 50.058 1.147 ;
     RECT  2.16 0.012 2.178 1.723 ;
     RECT  3.096 0.012 3.114 1.723 ;
     RECT  3.888 0.571 4.266 1.723 ;
     RECT  5.004 0.091 6.894 1.723 ;
     RECT  7.956 0.059 7.974 1.723 ;
     RECT  8.748 0.012 8.766 1.723 ;
     RECT  11.376 0.571 12.546 1.723 ;
     RECT  13.464 0.571 15.354 1.723 ;
     RECT  16.272 0.091 18.162 1.723 ;
     RECT  19.08 0.571 20.07 1.723 ;
     RECT  21.06 0.091 21.942 1.723 ;
     RECT  23.868 0.091 25.686 1.723 ;
     RECT  26.604 0.012 26.622 1.723 ;
     RECT  27.54 0.091 28.53 1.723 ;
     RECT  29.556 0.571 30.402 1.723 ;
     RECT  31.14 0.571 31.338 1.723 ;
     RECT  32.256 0.012 32.274 1.723 ;
     RECT  33.192 0.571 34.146 1.723 ;
     RECT  35.064 0.012 35.082 1.723 ;
     RECT  36.036 0.571 36.99 1.723 ;
     RECT  37.908 0.571 38.862 1.723 ;
     RECT  39.78 0.012 39.798 1.723 ;
     RECT  40.716 0.012 40.734 1.723 ;
     RECT  41.652 0.012 41.67 1.723 ;
     RECT  42.588 0.012 42.606 1.723 ;
     RECT  43.56 0.012 43.578 1.723 ;
     RECT  44.496 0.012 44.514 1.723 ;
     RECT  45.432 0.012 45.45 1.723 ;
     RECT  46.368 0.571 47.322 1.723 ;
     RECT  48.24 0.012 48.258 1.723 ;
     RECT  49.176 0.012 49.194 1.723 ;
     RECT  22.86 0.012 22.878 1.759 ;
     RECT  19.08 1.723 21.942 1.831 ;
     RECT  22.788 1.759 22.878 1.831 ;
     RECT  23.868 1.723 30.402 1.831 ;
     RECT  9.504 0.571 10.638 1.921 ;
     RECT  11.376 1.723 18.162 1.921 ;
     RECT  19.08 1.831 22.878 1.921 ;
     RECT  23.796 1.831 30.402 1.921 ;
     RECT  2.16 1.723 3.114 1.957 ;
     RECT  3.888 1.723 8.766 1.957 ;
     RECT  50.04 1.147 50.598 1.963 ;
     RECT  9.504 1.921 18.162 2.011 ;
     RECT  19.08 1.921 30.402 2.011 ;
     RECT  2.16 1.957 8.766 2.191 ;
     RECT  9.504 2.011 30.402 2.191 ;
     RECT  31.14 1.723 49.194 2.191 ;
     RECT  2.16 2.191 49.194 2.251 ;
     RECT  50.04 1.963 50.67 2.251 ;
     RECT  1.224 0.012 1.242 2.669 ;
     RECT  2.16 2.251 50.67 2.759 ;
     RECT  2.16 2.759 9.882 2.831 ;
     RECT  2.16 2.831 4.914 2.875 ;
     RECT  10.836 2.759 50.67 2.903 ;
     RECT  5.76 2.831 9.882 3.065 ;
     RECT  10.836 2.903 13.626 3.065 ;
     RECT  14.4 2.903 50.67 3.065 ;
     RECT  10.836 3.065 11.574 3.101 ;
     RECT  9.684 3.065 9.774 3.137 ;
     RECT  11.412 3.101 11.574 3.137 ;
     RECT  12.384 3.065 13.626 3.137 ;
     RECT  14.4 3.065 20.034 3.137 ;
     RECT  11.412 3.137 11.43 3.173 ;
     RECT  14.4 3.137 19.53 3.173 ;
     RECT  20.808 3.065 50.67 3.371 ;
     RECT  1.692 2.875 4.914 3.407 ;
     RECT  2.16 3.407 4.914 3.443 ;
     RECT  2.16 3.443 3.186 3.605 ;
     RECT  2.16 3.605 3.078 3.641 ;
     RECT  2.16 3.641 2.697 3.749 ;
     RECT  4.032 3.443 4.914 3.839 ;
     RECT  23.4 3.371 50.67 3.839 ;
     RECT  23.4 3.839 49.554 4.181 ;
     RECT  36.972 4.181 49.554 4.379 ;
     RECT  36.972 4.379 49.086 4.541 ;
     RECT  23.4 4.181 36.162 4.649 ;
     RECT  38.772 4.541 49.086 4.721 ;
     RECT  38.772 4.721 42.786 4.757 ;
     RECT  2.415 3.749 2.697 4.765 ;
     RECT  4.572 3.839 4.914 4.765 ;
     RECT  5.76 3.065 8.802 4.765 ;
     RECT  2.304 4.765 2.697 4.829 ;
     RECT  4.572 4.765 8.802 4.919 ;
     RECT  36.972 4.541 38.034 4.919 ;
     RECT  38.772 4.757 39.33 4.919 ;
     RECT  3.744 4.801 3.762 4.955 ;
     RECT  23.4 4.649 35.334 4.991 ;
     RECT  39.024 4.919 39.33 4.991 ;
     RECT  36.144 4.649 36.162 5.071 ;
     RECT  36.972 4.919 37.854 5.071 ;
     RECT  40.176 4.757 42.786 5.225 ;
     RECT  4.572 4.919 4.914 5.369 ;
     RECT  43.524 4.721 49.086 5.459 ;
     RECT  50.652 3.839 50.67 5.531 ;
     RECT  41.364 5.225 42.786 5.639 ;
     RECT  47.7 5.459 49.086 6.151 ;
     RECT  47.7 6.151 49.158 6.179 ;
     RECT  43.524 5.459 46.854 6.269 ;
     RECT  4.896 5.369 4.914 6.449 ;
     RECT  47.952 6.179 49.158 6.511 ;
     RECT  9.756 3.137 9.774 6.539 ;
     RECT  6.012 4.919 8.802 6.691 ;
     RECT  50.688 5.947 50.706 6.719 ;
     RECT  47.952 6.511 49.374 6.809 ;
     RECT  20.808 3.371 22.302 6.817 ;
     RECT  13.215 3.137 13.626 6.845 ;
     RECT  47.952 6.809 49.194 6.845 ;
     RECT  6.012 6.691 9.486 6.953 ;
     RECT  6.516 6.953 9.486 6.989 ;
     RECT  5.508 6.961 5.526 7.079 ;
     RECT  4.572 7.189 4.59 7.229 ;
     RECT  2.415 4.829 2.697 7.231 ;
     RECT  3.6 5.467 3.618 7.231 ;
     RECT  2.415 7.231 3.618 7.349 ;
     RECT  47.952 6.845 49.158 7.349 ;
     RECT  50.076 7.291 50.094 7.421 ;
     RECT  6.516 6.989 8.802 7.889 ;
     RECT  43.524 6.269 46.71 8.005 ;
     RECT  51.732 7.963 51.75 8.093 ;
     RECT  43.524 8.005 47.07 8.159 ;
     RECT  50.688 8.059 50.706 8.231 ;
     RECT  48.24 7.349 49.158 8.581 ;
     RECT  48.06 8.581 49.158 8.699 ;
     RECT  50.076 8.635 50.094 8.771 ;
     RECT  20.736 6.817 22.302 8.941 ;
     RECT  23.4 4.991 35.298 8.941 ;
     RECT  40.176 5.225 40.59 8.971 ;
     RECT  41.364 5.639 42.498 8.971 ;
     RECT  40.176 8.971 42.498 9.239 ;
     RECT  50.652 9.307 50.67 9.383 ;
     RECT  48.24 8.699 49.158 9.391 ;
     RECT  48.24 9.391 49.266 9.509 ;
     RECT  43.524 8.159 46.71 9.661 ;
     RECT  6.732 7.889 8.802 9.815 ;
     RECT  43.524 9.661 47.286 9.821 ;
     RECT  20.736 8.941 35.298 9.959 ;
     RECT  6.588 9.925 6.606 9.965 ;
     RECT  50.688 9.895 50.706 9.965 ;
     RECT  48.24 9.509 49.158 10.471 ;
     RECT  48.06 10.471 49.158 10.589 ;
     RECT  48.204 10.589 49.158 10.603 ;
     RECT  48.204 10.603 49.59 10.661 ;
     RECT  11.376 10.741 11.394 10.895 ;
     RECT  7.815 9.815 8.802 10.967 ;
     RECT  10.476 10.939 10.494 11.011 ;
     RECT  10.404 11.011 10.494 11.039 ;
     RECT  43.524 9.821 46.71 11.101 ;
     RECT  50.688 11.245 50.706 11.309 ;
     RECT  48.204 10.661 49.158 11.399 ;
     RECT  43.308 11.101 46.71 11.579 ;
     RECT  20.736 9.959 22.302 11.749 ;
     RECT  23.4 9.959 35.298 11.749 ;
     RECT  4.716 9.517 4.734 11.821 ;
     RECT  43.524 11.579 46.71 11.899 ;
     RECT  43.524 11.899 47.106 11.939 ;
     RECT  50.148 11.947 50.166 11.984 ;
     RECT  20.736 11.749 35.298 12.091 ;
     RECT  13.215 6.845 13.554 12.361 ;
     RECT  14.4 3.173 16.83 12.361 ;
     RECT  2.415 7.349 2.697 12.427 ;
     RECT  10.404 11.039 10.422 12.451 ;
     RECT  3.6 7.349 3.618 12.487 ;
     RECT  2.304 12.427 2.697 12.515 ;
     RECT  10.404 12.451 10.71 12.559 ;
     RECT  20.592 12.091 35.298 12.559 ;
     RECT  48.24 11.399 49.158 12.559 ;
     RECT  10.404 12.559 10.854 12.595 ;
     RECT  12.384 3.137 12.402 12.595 ;
     RECT  13.215 12.361 16.83 12.595 ;
     RECT  17.604 3.173 19.53 12.595 ;
     RECT  20.268 12.559 35.298 12.595 ;
     RECT  10.404 12.595 11.466 12.715 ;
     RECT  43.524 11.939 46.71 12.715 ;
     RECT  17.604 12.595 35.298 12.749 ;
     RECT  43.524 12.715 47.322 12.755 ;
     RECT  12.384 12.595 16.83 12.757 ;
     RECT  17.604 12.749 26.874 12.757 ;
     RECT  10.404 12.715 11.646 12.793 ;
     RECT  12.384 12.757 26.874 12.793 ;
     RECT  7.815 10.967 8.097 12.901 ;
     RECT  3.6 12.487 3.978 12.991 ;
     RECT  4.716 11.821 5.31 12.991 ;
     RECT  7.776 12.901 8.097 13.003 ;
     RECT  7.776 13.003 8.478 13.051 ;
     RECT  9.216 12.991 9.234 13.051 ;
     RECT  2.415 12.515 2.697 13.063 ;
     RECT  3.6 12.991 5.31 13.063 ;
     RECT  48.132 12.559 49.158 13.063 ;
     RECT  7.776 13.051 9.234 13.093 ;
     RECT  7.776 13.093 9.378 13.099 ;
     RECT  2.415 13.063 5.31 13.135 ;
     RECT  6.66 12.991 6.678 13.135 ;
     RECT  7.452 13.099 9.558 13.135 ;
     RECT  10.404 12.793 26.874 13.135 ;
     RECT  48.132 13.063 49.878 13.171 ;
     RECT  2.415 13.135 6.678 13.297 ;
     RECT  7.416 13.135 26.874 13.297 ;
     RECT  50.652 12.619 50.67 13.631 ;
     RECT  2.415 13.297 26.874 13.639 ;
     RECT  27.72 12.749 35.298 13.639 ;
     RECT  43.524 12.755 46.71 13.639 ;
     RECT  41.364 9.239 42.498 13.675 ;
     RECT  43.452 13.639 46.71 13.675 ;
     RECT  2.415 13.639 35.298 13.711 ;
     RECT  41.364 13.675 46.71 13.771 ;
     RECT  2.376 13.711 35.298 13.901 ;
     RECT  50.688 13.909 50.706 13.949 ;
     RECT  41.364 13.771 46.782 13.981 ;
     RECT  47.988 13.171 49.878 13.981 ;
     RECT  7.416 13.901 35.298 14.143 ;
     RECT  36.144 5.071 37.854 14.143 ;
     RECT  40.176 9.239 40.59 14.215 ;
     RECT  39.024 4.991 39.042 14.251 ;
     RECT  39.924 14.215 40.59 14.251 ;
     RECT  39.024 14.251 40.59 14.341 ;
     RECT  41.364 13.981 49.878 14.341 ;
     RECT  39.024 14.341 49.878 14.449 ;
     RECT  38.772 14.449 49.878 14.485 ;
     RECT  7.416 14.143 37.854 14.521 ;
     RECT  38.664 14.485 49.878 14.521 ;
     RECT  2.376 13.901 6.678 14.647 ;
     RECT  1.98 14.647 6.678 14.791 ;
     RECT  7.416 14.521 49.878 14.791 ;
     RECT  1.98 14.791 49.878 14.909 ;
     RECT  29.016 14.909 49.878 14.981 ;
     RECT  26.496 14.909 28.278 15.017 ;
     RECT  45.576 14.981 49.878 15.025 ;
     RECT  7.704 14.909 8.19 15.101 ;
     RECT  8.964 14.909 19.746 15.101 ;
     RECT  45.576 15.025 50.202 15.101 ;
     RECT  7.704 15.101 7.905 15.137 ;
     RECT  8.964 15.101 19.206 15.137 ;
     RECT  8.964 15.137 18.45 15.245 ;
     RECT  14.076 15.245 18.45 15.293 ;
     RECT  47.304 15.101 50.202 15.293 ;
     RECT  1.98 14.909 5.67 15.389 ;
     RECT  6.408 14.909 6.966 15.389 ;
     RECT  8.964 15.245 12.834 15.389 ;
     RECT  14.076 15.293 17.946 15.389 ;
     RECT  20.484 14.909 25.614 15.389 ;
     RECT  29.016 14.981 31.194 15.389 ;
     RECT  31.968 14.981 42.21 15.389 ;
     RECT  45.576 15.101 46.062 15.389 ;
     RECT  31.968 15.389 35.838 15.437 ;
     RECT  37.08 15.389 40.95 15.437 ;
     RECT  47.304 15.293 49.878 15.437 ;
     RECT  26.496 15.017 28.17 15.965 ;
     RECT  31.968 15.437 33.282 15.965 ;
     RECT  42.984 14.981 44.766 15.965 ;
     RECT  48.6 15.437 49.878 15.965 ;
     RECT  30.708 15.389 31.194 16.013 ;
     RECT  37.08 15.437 38.394 16.541 ;
     RECT  15.372 15.389 16.65 16.589 ;
     RECT  48.6 15.965 48.87 16.589 ;
     RECT  5.148 15.389 5.67 17.165 ;
     RECT  34.524 15.437 35.838 17.165 ;
     RECT  39.636 15.437 40.95 17.165 ;
     RECT  43.488 15.965 44.766 17.165 ;
     RECT  1.296 17.179 1.314 17.261 ;
     RECT  2.592 15.389 2.61 17.261 ;
     RECT  3.852 15.389 3.87 17.261 ;
     RECT  5.148 17.165 5.166 17.261 ;
     RECT  6.408 15.389 6.426 17.261 ;
     RECT  7.704 15.137 7.722 17.261 ;
     RECT  8.964 15.389 8.982 17.261 ;
     RECT  10.26 15.389 10.278 17.261 ;
     RECT  11.52 15.389 11.538 17.261 ;
     RECT  12.816 15.389 12.834 17.261 ;
     RECT  14.076 15.389 14.094 17.261 ;
     RECT  15.372 16.589 15.39 17.261 ;
     RECT  16.632 16.589 16.65 17.261 ;
     RECT  17.928 15.389 17.946 17.261 ;
     RECT  19.188 15.137 19.206 17.261 ;
     RECT  20.484 15.389 20.502 17.261 ;
     RECT  21.744 15.389 21.762 17.261 ;
     RECT  23.04 15.389 23.058 17.261 ;
     RECT  24.3 15.389 24.318 17.261 ;
     RECT  25.596 15.389 25.614 17.261 ;
     RECT  26.856 15.965 26.874 17.261 ;
     RECT  28.152 15.965 28.17 17.261 ;
     RECT  29.412 15.389 29.43 17.261 ;
     RECT  30.708 16.013 30.726 17.261 ;
     RECT  31.968 15.965 31.986 17.261 ;
     RECT  33.264 15.965 33.282 17.261 ;
     RECT  34.524 17.165 34.542 17.261 ;
     RECT  35.82 17.165 35.838 17.261 ;
     RECT  37.08 16.541 37.098 17.261 ;
     RECT  38.376 16.541 38.394 17.261 ;
     RECT  39.636 17.165 39.654 17.261 ;
     RECT  40.932 17.165 40.95 17.261 ;
     RECT  42.192 15.389 42.21 17.261 ;
     RECT  43.488 17.165 43.506 17.261 ;
     RECT  44.748 17.165 44.766 17.261 ;
     RECT  46.044 15.389 46.062 17.261 ;
     RECT  47.304 15.437 47.322 17.261 ;
     RECT  48.6 16.589 48.618 17.261 ;
     RECT  49.86 15.965 49.878 17.261 ;
    LAYER M4 ;
     RECT  1.244 17.184 1.331 17.208 ;
     RECT  0.06 2.256 1.637 2.28 ;
     RECT  0.06 14.976 1.925 15 ;
     RECT  1.925 14.976 2.009 15.384 ;
     RECT  1.637 2.256 2.408 2.904 ;
     RECT  0.06 4.8 2.408 4.824 ;
     RECT  0.06 7.344 2.408 7.368 ;
     RECT  1.285 8.736 2.408 8.76 ;
     RECT  0.06 9.888 2.408 9.912 ;
     RECT  0.06 12.432 2.408 12.456 ;
     RECT  2.009 14.976 2.408 15.132 ;
     RECT  2.408 2.148 2.629 15.132 ;
     RECT  2.629 1.728 2.704 15.132 ;
     RECT  2.704 1.728 2.765 1.752 ;
     RECT  3.205 15.36 3.305 15.384 ;
     RECT  2.704 13.632 3.74 13.896 ;
     RECT  3.74 13.632 3.827 14.328 ;
     RECT  3.541 0.576 3.917 0.6 ;
     RECT  3.827 13.632 3.932 13.896 ;
     RECT  3.932 13.2 3.973 13.896 ;
     RECT  4.481 1.728 4.565 1.752 ;
     RECT  4.481 15.36 4.565 15.384 ;
     RECT  3.973 13.104 5.285 13.896 ;
     RECT  3.913 3.312 5.411 3.336 ;
     RECT  5.209 4.8 5.411 4.824 ;
     RECT  4.561 7.2 5.411 7.224 ;
     RECT  5.641 17.136 5.795 17.16 ;
     RECT  5.461 0.096 6.445 0.12 ;
     RECT  5.285 13.536 6.613 13.896 ;
     RECT  5.365 9.936 6.659 9.96 ;
     RECT  6.937 15.36 7.091 15.384 ;
     RECT  6.613 13.056 7.765 13.896 ;
     RECT  7.325 1.728 7.808 1.752 ;
     RECT  2.704 8.736 7.808 8.76 ;
     RECT  7.765 13.056 7.808 13.944 ;
     RECT  7.808 1.728 7.912 15.132 ;
     RECT  7.912 1.728 8.104 15.096 ;
     RECT  8.104 1.728 8.309 1.752 ;
     RECT  8.104 15.072 8.387 15.096 ;
     RECT  9.205 0.576 9.533 0.6 ;
     RECT  9.589 15.36 9.677 15.384 ;
     RECT  10.069 0.528 10.211 0.552 ;
     RECT  8.104 13.008 10.393 13.896 ;
     RECT  10.825 2.832 10.973 2.856 ;
     RECT  10.885 15.36 10.973 15.384 ;
     RECT  10.393 12.432 11.413 13.896 ;
     RECT  11.413 12.432 11.459 14.088 ;
     RECT  11.365 10.8 11.555 10.824 ;
     RECT  11.459 12.528 11.621 14.088 ;
     RECT  11.621 12.528 12.053 13.464 ;
     RECT  11.077 0.576 12.269 0.6 ;
     RECT  12.181 15.36 12.269 15.384 ;
     RECT  12.053 12.528 13.057 13.176 ;
     RECT  12.949 1.728 13.097 1.752 ;
     RECT  8.104 8.736 13.208 8.76 ;
     RECT  13.057 12.528 13.208 13.704 ;
     RECT  13.208 2.148 13.312 15.132 ;
     RECT  13.312 2.418 13.345 15.132 ;
     RECT  13.345 2.418 13.475 15.24 ;
     RECT  13.475 2.418 13.504 14.862 ;
     RECT  13.909 0.096 14.213 0.12 ;
     RECT  14.713 15.36 14.797 15.384 ;
     RECT  13.504 12.432 14.857 13.704 ;
     RECT  14.857 12.432 14.861 14.136 ;
     RECT  14.861 12.528 14.969 14.136 ;
     RECT  14.969 13.632 15.041 14.136 ;
     RECT  14.869 0.576 15.077 0.6 ;
     RECT  15.781 1.728 15.869 1.752 ;
     RECT  14.969 12.528 15.937 12.552 ;
     RECT  15.041 13.632 15.937 13.704 ;
     RECT  15.937 12.528 16.013 13.704 ;
     RECT  15.932 16.56 16.019 16.584 ;
     RECT  16.081 2.832 16.193 2.856 ;
     RECT  17.197 15.36 17.315 15.384 ;
     RECT  16.013 12.528 17.417 13.656 ;
     RECT  16.741 0.096 17.849 0.12 ;
     RECT  17.417 12.528 18.421 12.552 ;
     RECT  17.417 13.584 18.421 13.656 ;
     RECT  18.133 2.544 18.565 2.568 ;
     RECT  18.565 2.016 18.608 2.568 ;
     RECT  13.504 8.736 18.608 8.76 ;
     RECT  18.421 12.528 18.608 13.656 ;
     RECT  18.421 15.264 18.608 15.288 ;
     RECT  18.608 2.016 18.611 15.288 ;
     RECT  18.611 2.016 18.659 15.132 ;
     RECT  18.659 2.148 18.712 15.132 ;
     RECT  18.712 2.418 18.904 14.862 ;
     RECT  18.904 12.432 19.757 13.656 ;
     RECT  19.573 0.576 19.793 0.6 ;
     RECT  19.717 15.072 19.859 15.096 ;
     RECT  20.473 1.728 20.557 1.752 ;
     RECT  19.757 13.632 21.157 13.656 ;
     RECT  21.085 15.36 21.169 15.384 ;
     RECT  21.157 13.632 21.244 14.376 ;
     RECT  21.445 0.096 21.529 0.12 ;
     RECT  18.904 8.736 22.021 8.76 ;
     RECT  19.757 12.432 22.133 12.456 ;
     RECT  21.244 13.632 22.277 13.656 ;
     RECT  22.373 15.36 22.457 15.384 ;
     RECT  22.357 2.112 22.817 2.136 ;
     RECT  22.705 12.528 23.245 12.552 ;
     RECT  23.653 15.36 23.753 15.384 ;
     RECT  23.276 2.256 24.008 2.28 ;
     RECT  22.021 8.736 24.008 9.048 ;
     RECT  23.245 12.432 24.008 12.552 ;
     RECT  24.008 2.148 24.112 15.132 ;
     RECT  24.112 2.418 24.304 15.132 ;
     RECT  24.229 0.096 24.437 0.12 ;
     RECT  24.304 12.528 24.473 12.552 ;
     RECT  24.929 15.36 25.013 15.384 ;
     RECT  25.148 1.104 25.235 1.128 ;
     RECT  24.304 8.736 25.657 9.048 ;
     RECT  25.657 8.544 25.697 9.048 ;
     RECT  24.304 13.632 25.697 13.656 ;
     RECT  26.197 15.936 26.525 15.96 ;
     RECT  26.125 2.784 26.773 2.808 ;
     RECT  26.149 1.728 27.317 1.752 ;
     RECT  27.493 15.936 27.605 15.96 ;
     RECT  26.773 2.736 27.781 2.808 ;
     RECT  27.781 2.688 27.857 2.808 ;
     RECT  27.989 0.096 28.073 0.12 ;
     RECT  27.857 2.688 28.361 2.712 ;
     RECT  28.925 1.728 29.009 1.752 ;
     RECT  25.873 3.84 29.408 3.864 ;
     RECT  25.697 8.544 29.408 8.568 ;
     RECT  28.789 15.36 29.408 15.384 ;
     RECT  29.408 2.148 29.512 15.384 ;
     RECT  29.512 2.418 29.704 15.384 ;
     RECT  29.704 14.832 30.089 15.384 ;
     RECT  30.089 14.832 30.773 14.856 ;
     RECT  29.893 0.576 31.169 0.6 ;
     RECT  31.165 15.984 31.379 16.008 ;
     RECT  29.704 3.84 31.417 3.864 ;
     RECT  31.417 3.84 31.813 4.584 ;
     RECT  31.813 3.36 31.907 4.584 ;
     RECT  32.597 15.936 32.681 15.96 ;
     RECT  31.733 1.728 32.771 1.752 ;
     RECT  31.907 3.36 33.217 3.96 ;
     RECT  33.613 0.576 33.697 0.6 ;
     RECT  33.836 15.408 33.923 15.432 ;
     RECT  33.217 3.36 34.585 4.296 ;
     RECT  34.585 1.728 34.808 1.752 ;
     RECT  34.585 3.36 34.808 4.536 ;
     RECT  29.704 8.544 34.808 8.568 ;
     RECT  34.808 1.728 34.912 15.132 ;
     RECT  34.912 1.728 35.104 14.862 ;
     RECT  35.173 17.136 35.273 17.16 ;
     RECT  35.104 1.728 35.603 1.752 ;
     RECT  35.104 3.36 36.173 4.536 ;
     RECT  36.173 3.36 36.425 3.96 ;
     RECT  36.413 15.36 36.497 15.384 ;
     RECT  36.449 0.576 36.533 0.6 ;
     RECT  37.285 1.728 37.421 1.752 ;
     RECT  36.425 3.408 37.429 3.96 ;
     RECT  37.421 1.728 37.475 2.28 ;
     RECT  37.429 3.408 37.753 4.392 ;
     RECT  37.717 16.512 37.801 16.536 ;
     RECT  37.475 2.256 37.811 2.28 ;
     RECT  37.753 3.408 38.225 4.536 ;
     RECT  38.257 0.576 38.387 0.6 ;
     RECT  38.905 15.408 39.059 15.432 ;
     RECT  39.301 1.728 40.208 1.752 ;
     RECT  38.225 3.408 40.208 4.44 ;
     RECT  35.104 8.544 40.208 8.568 ;
     RECT  40.208 1.728 40.312 15.132 ;
     RECT  40.261 17.136 40.385 17.16 ;
     RECT  40.312 1.728 40.504 14.862 ;
     RECT  40.504 2.832 40.835 2.856 ;
     RECT  40.504 3.84 40.883 5.208 ;
     RECT  40.883 5.184 41.027 5.208 ;
     RECT  40.504 8.544 41.027 9.144 ;
     RECT  41.525 15.36 41.609 15.384 ;
     RECT  40.883 3.84 42.037 3.96 ;
     RECT  41.027 9.12 42.181 9.144 ;
     RECT  42.181 9.12 42.227 9.96 ;
     RECT  42.181 11.424 42.401 11.448 ;
     RECT  42.037 3.456 42.541 3.96 ;
     RECT  42.853 15.936 43.013 15.96 ;
     RECT  42.541 3.072 43.657 3.96 ;
     RECT  43.657 2.832 43.909 3.96 ;
     RECT  42.073 5.184 43.909 5.208 ;
     RECT  43.909 2.832 43.955 5.208 ;
     RECT  43.955 3.024 44.021 5.208 ;
     RECT  44.101 17.136 44.237 17.16 ;
     RECT  44.732 8.832 44.773 8.856 ;
     RECT  42.227 9.936 44.773 9.96 ;
     RECT  45.397 15.36 45.605 15.384 ;
     RECT  40.504 1.728 45.608 1.752 ;
     RECT  44.021 3.024 45.608 3.96 ;
     RECT  44.773 8.448 45.608 8.856 ;
     RECT  44.773 9.936 45.608 10.584 ;
     RECT  42.577 13.872 45.608 13.896 ;
     RECT  45.608 1.728 45.712 15.132 ;
     RECT  45.712 1.728 45.904 15.096 ;
     RECT  45.904 1.728 45.923 1.752 ;
     RECT  45.904 6.528 46.019 7.416 ;
     RECT  45.904 8.448 46.109 8.472 ;
     RECT  45.904 15.072 46.757 15.096 ;
     RECT  45.904 13.776 46.793 13.896 ;
     RECT  46.753 0.576 46.883 0.6 ;
     RECT  47.036 11.904 47.077 11.928 ;
     RECT  47.077 11.904 47.123 12.744 ;
     RECT  46.793 13.776 47.123 13.8 ;
     RECT  45.904 9.792 47.297 9.816 ;
     RECT  47.123 12.72 47.333 12.744 ;
     RECT  45.904 3.024 47.765 4.824 ;
     RECT  47.765 3.456 47.801 4.824 ;
     RECT  47.9 15.408 47.987 15.432 ;
     RECT  46.019 6.528 48.089 6.552 ;
     RECT  47.801 3.84 48.665 4.824 ;
     RECT  47.581 1.728 48.755 1.752 ;
     RECT  48.665 4.8 48.917 4.824 ;
     RECT  48.841 16.56 49.283 16.584 ;
     RECT  49.58 2.256 49.667 2.28 ;
     RECT  49.165 14.256 49.777 14.28 ;
     RECT  49.777 14.256 50.173 14.616 ;
     RECT  49.309 15.936 50.173 15.96 ;
     RECT  50.137 1.344 50.569 1.368 ;
     RECT  50.569 1.152 50.641 1.368 ;
     RECT  50.101 2.64 50.641 2.664 ;
     RECT  50.065 8.64 50.641 8.664 ;
     RECT  50.137 11.952 50.641 11.976 ;
     RECT  50.173 14.256 50.641 15.96 ;
     RECT  50.641 1.152 50.653 5.352 ;
     RECT  50.653 1.344 50.677 5.352 ;
     RECT  50.065 7.296 50.677 7.32 ;
     RECT  50.641 8.64 50.677 9.336 ;
     RECT  49.561 10.608 50.677 10.632 ;
     RECT  50.641 11.952 50.677 15.96 ;
     RECT  50.677 1.344 51.804 15.96 ;
    LAYER M5 ;
     RECT  1.68 0.016 50.616 0.131 ;
     RECT  7.344 0.131 12.984 0.563 ;
     RECT  1.68 0.131 4.536 0.611 ;
     RECT  7.344 0.563 9.24 0.611 ;
     RECT  11.088 0.563 12.984 0.611 ;
     RECT  14.88 0.131 15.816 0.611 ;
     RECT  18.624 0.131 20.52 0.611 ;
     RECT  28.944 0.131 50.616 0.611 ;
     RECT  25.2 0.131 27.096 1.139 ;
     RECT  47.76 0.611 50.616 1.187 ;
     RECT  4.512 0.611 4.536 1.763 ;
     RECT  7.344 0.611 8.28 1.763 ;
     RECT  12.96 0.611 12.984 1.763 ;
     RECT  15.792 0.611 15.816 1.763 ;
     RECT  20.496 0.611 20.52 1.763 ;
     RECT  26.16 1.139 27.096 1.763 ;
     RECT  28.944 0.611 28.968 1.763 ;
     RECT  31.776 0.611 32.76 1.763 ;
     RECT  34.608 0.611 35.592 1.763 ;
     RECT  39.312 0.611 45.912 1.763 ;
     RECT  47.76 1.187 49.656 1.763 ;
     RECT  18.624 0.611 18.648 2.137 ;
     RECT  22.368 0.131 23.352 2.137 ;
     RECT  22.368 2.137 24.12 2.147 ;
     RECT  1.68 0.611 2.664 2.151 ;
     RECT  13.2 2.137 13.32 2.151 ;
     RECT  18.6 2.137 18.72 2.151 ;
     RECT  23.328 2.147 24.12 2.151 ;
     RECT  29.4 2.137 29.52 2.151 ;
     RECT  37.44 0.611 37.464 2.245 ;
     RECT  23.328 2.151 24.312 2.291 ;
     RECT  49.632 1.763 49.656 2.291 ;
     RECT  40.2 1.763 40.512 2.821 ;
     RECT  1.68 2.151 2.712 2.915 ;
     RECT  37.44 2.245 37.8 3.971 ;
     RECT  37.44 3.971 37.464 4.403 ;
     RECT  40.2 2.821 40.824 4.405 ;
     RECT  31.872 3.589 31.896 4.595 ;
     RECT  43.92 2.821 43.944 4.595 ;
     RECT  40.2 4.405 40.872 5.173 ;
     RECT  45.6 1.763 45.912 6.517 ;
     RECT  45.6 6.517 46.008 8.437 ;
     RECT  44.784 8.437 46.008 8.483 ;
     RECT  40.2 5.173 41.016 9.011 ;
     RECT  5.376 3.301 5.4 9.971 ;
     RECT  44.784 8.483 45.912 10.595 ;
     RECT  42.192 9.109 42.216 11.459 ;
     RECT  11.52 10.789 11.544 12.421 ;
     RECT  22.032 9.013 22.056 12.467 ;
     RECT  11.424 12.421 11.544 12.517 ;
     RECT  18.6 2.151 18.912 12.517 ;
     RECT  13.2 2.151 13.512 12.757 ;
     RECT  11.328 12.517 11.544 12.803 ;
     RECT  6.624 9.925 6.648 13.091 ;
     RECT  11.424 12.803 11.544 13.091 ;
     RECT  3.984 13.093 4.008 13.235 ;
     RECT  13.2 12.757 13.608 13.331 ;
     RECT  18.6 12.517 19.32 13.667 ;
     RECT  9.696 13.045 9.72 13.811 ;
     RECT  47.088 9.781 47.112 13.811 ;
     RECT  11.424 13.091 11.448 14.099 ;
     RECT  3.792 13.861 3.816 14.339 ;
     RECT  21.168 13.621 21.192 14.387 ;
     RECT  7.8 1.763 8.112 15.061 ;
     RECT  18.6 13.667 18.912 15.061 ;
     RECT  45.6 10.595 45.912 15.061 ;
     RECT  13.2 13.331 13.512 15.129 ;
     RECT  18.6 15.061 19.848 15.129 ;
     RECT  34.8 1.763 35.112 15.129 ;
     RECT  40.2 9.011 40.512 15.129 ;
     RECT  2.4 2.915 2.712 15.143 ;
     RECT  7.8 15.061 8.376 15.143 ;
     RECT  13.2 15.129 13.464 15.143 ;
     RECT  18.6 15.129 18.72 15.143 ;
     RECT  24 2.291 24.312 15.143 ;
     RECT  29.4 2.151 29.712 15.143 ;
     RECT  34.8 15.129 34.92 15.143 ;
     RECT  40.2 15.129 40.32 15.143 ;
     RECT  45.6 15.061 46.68 15.143 ;
     RECT  1.296 8.725 1.32 15.349 ;
     RECT  1.296 15.349 1.992 17.219 ;
     RECT  1.968 17.219 1.992 17.232 ;
     RECT  3.216 15.349 3.24 17.232 ;
     RECT  4.512 15.349 4.536 17.232 ;
     RECT  5.76 17.125 5.784 17.232 ;
     RECT  7.056 15.349 7.08 17.232 ;
     RECT  8.352 15.143 8.376 17.232 ;
     RECT  9.6 15.349 9.624 17.232 ;
     RECT  10.896 15.349 10.92 17.232 ;
     RECT  12.192 15.349 12.216 17.232 ;
     RECT  13.44 15.143 13.464 17.232 ;
     RECT  14.736 15.349 14.76 17.232 ;
     RECT  15.984 16.549 16.008 17.232 ;
     RECT  17.28 15.349 17.304 17.232 ;
     RECT  18.576 15.253 18.6 17.232 ;
     RECT  19.824 15.129 19.848 17.232 ;
     RECT  21.12 15.349 21.144 17.232 ;
     RECT  22.416 15.349 22.44 17.232 ;
     RECT  23.664 15.349 23.688 17.232 ;
     RECT  24.96 15.349 24.984 17.232 ;
     RECT  26.208 15.925 26.232 17.232 ;
     RECT  27.504 15.925 27.528 17.232 ;
     RECT  28.8 15.349 28.824 17.232 ;
     RECT  30.048 15.349 30.072 17.232 ;
     RECT  31.344 15.973 31.368 17.232 ;
     RECT  32.64 15.925 32.664 17.232 ;
     RECT  33.888 15.397 33.912 17.232 ;
     RECT  35.184 17.125 35.208 17.232 ;
     RECT  36.432 15.349 36.456 17.232 ;
     RECT  37.728 16.501 37.752 17.232 ;
     RECT  39.024 15.397 39.048 17.232 ;
     RECT  40.272 17.125 40.296 17.232 ;
     RECT  41.568 15.349 41.592 17.232 ;
     RECT  42.864 15.925 42.888 17.232 ;
     RECT  44.112 17.125 44.136 17.232 ;
     RECT  45.408 15.349 45.432 17.232 ;
     RECT  46.656 15.143 46.68 17.232 ;
     RECT  47.952 15.397 47.976 17.232 ;
     RECT  49.248 16.549 49.272 17.232 ;
     RECT  50.496 14.245 50.52 17.232 ;
  END
END qkd_static_kv_landing_relay
END LIBRARY
